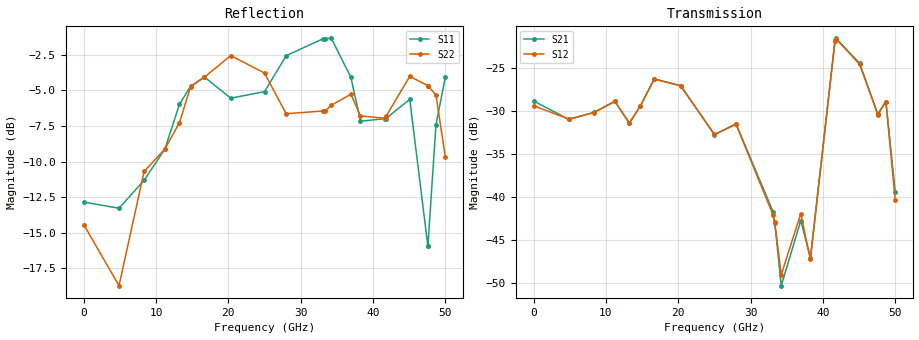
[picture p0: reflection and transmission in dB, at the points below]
!Keysight Technologies,N5245B,MY58422270,A.16.20.02
!Date: Thursday, March 05, 2026 01:39:43
!Correction: S11(C  2-Port  )
!S21(C  2-Port  )
!S12(C  2-Port  )
!S22(C  2-Port  )
!S2P File: Measurements: S11, S21, S12, S22:
# Hz S  dB  R 50
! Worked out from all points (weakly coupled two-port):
!   3201 points, 10 MHz to 50 GHz, reference 50 ohm
!   highest |S21| = -21.55 dB at 41.8 GHz (marker M1); lowest = -50.3 dB at 34.24 GHz (marker M2)
!   lowest |S11| = -15.9 dB at 47.58 GHz (marker M3), VSWR 1.38, Z = 45.2 + j14.6 ohm
!   |S11| at or under -10 dB: start of sweep to 9.793 GHz; 11.44 GHz to 11.86 GHz (420.2 MHz wide, 3.61 % of centre); 46.75 GHz to 48.31 GHz (1.559 GHz wide, 3.28 % of centre)
!   |S22| runs from -18.8 to -2.5 dB; largest |S21 - S12| = 0.013
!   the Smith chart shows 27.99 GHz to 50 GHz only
!   S11 on the Smith chart (normalised r, x): 27.99 GHz: 0.20, +0.57; 33.13 GHz: 0.67, +2.66; 36.94 GHz: 1.53, -1.91; 47.59 GHz: 0.92, +0.30; 50 GHz: 0.54, -1.09
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1e7  -12.85 -3.7  -28.83 6.3  -29.38 12.0  -14.43 36.0
4.884025e9  -13.28 -123.0  -30.97 177.1  -30.93 176.9  -18.72 -128.1
8.352081e9  -11.32 170.3  -30.14 32.4  -30.17 32.3  -10.70 -163.2
1.122651e10  -9.12 100.6  -28.87 -70.3  -28.88 -70.2  -9.12 88.4
1.324173e10  -5.98 60.4  -31.40 -119.0  -31.38 -118.7  -7.27 -20.4
1.477267e10  -4.72 13.0  -29.38 -146.7  -29.39 -147.0  -4.75 -89.5
1.667854e10  -4.06 -44.4  -26.26 158.3  -26.29 158.2  -4.08 -141.8
2.033406e10  -5.55 -126.8  -27.06 39.8  -27.05 39.6  -2.56 153.5
2.5005e10  -5.09 171.5  -32.73 -68.2  -32.71 -67.8  -3.79 70.6
2.798878e10  -2.57 119.3  -31.48 -132.5  -31.54 -133.4  -6.64 16.5
3.312838e10  -1.37 39.2  -41.73 12.5  -42.11 13.6  -6.45 -126.0
3.334708e10  -1.36 35.5  -43.03 -1.2  -42.93 -4.2  -6.47 -131.0
3.423753e10  -1.35 20.2  -50.28 -83.3  -49.01 -91.7  -6.05 -150.3
3.694011e10  -4.08 -37.5  -42.72 91.0  -41.91 100.9  -5.27 156.3
3.826797e10  -7.17 -20.5  -47.06 -40.4  -47.23 -172.3  -6.80 133.8
4.167354e10  -6.99 -56.4  -21.74 -61.2  -21.86 -60.7  -6.96 113.2
4.179852e10  -6.98 -56.5  -21.55 -72.7  -21.59 -72.3  -6.83 112.3
4.507911e10  -5.63 -105.2  -24.44 87.7  -24.57 88.3  -4.02 75.8
4.757861e10  -15.92 99.5  -30.35 -15.3  -30.38 -15.4  -4.67 42.2
4.759423e10  -15.90 96.8  -30.30 -15.3  -30.41 -15.6  -4.67 41.9
4.870338e10  -7.42 -25.4  -28.89 -90.7  -28.89 -90.7  -5.33 20.1
5e10  -4.07 -77.7  -39.41 -133.0  -40.38 -132.0  -9.68 6.9
